VERSION 5.7 ;
  NOWIREEXTENSIONATPIN ON ;
  DIVIDERCHAR "/" ;
  BUSBITCHARS "[]" ;
PROPERTYDEFINITIONS
  MACRO ALPHA STRING ;
  MACRO MASK STRING ;
  MACRO CDL STRING ;
  MACRO ZED STRING ;
END PROPERTYDEFINITIONS

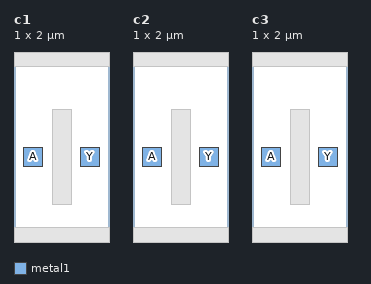
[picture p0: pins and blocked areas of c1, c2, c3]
MACRO c1
  CLASS BLOCK ;
  FOREIGN c1 ;
  ORIGIN 0.000 0.000 ;
  SIZE 1.000 BY 2.000 ;
  PIN A
    DIRECTION INPUT ;
    USE SIGNAL ;
    PORT
      LAYER metal1 ;
        RECT 0.100 0.800 0.300 1.000 ;
    END
  END A
  PIN Y
    DIRECTION OUTPUT ;
    USE SIGNAL ;
    PORT
      LAYER metal1 ;
        RECT 0.700 0.800 0.900 1.000 ;
    END
  END Y
  OBS
      LAYER metal1 ;
        RECT 0.000 1.850 1.000 2.000 ;
        RECT 0.400 0.400 0.600 1.400 ;
        RECT 0.000 0.000 1.000 0.150 ;
  END
  PROPERTY CDL c1 ;
  PROPERTY MASK 1 ;
END c1
MACRO c2
  CLASS BLOCK ;
  FOREIGN c2 ;
  ORIGIN 0.000 0.000 ;
  SIZE 1.000 BY 2.000 ;
  PIN A
    DIRECTION INPUT ;
    USE SIGNAL ;
    PORT
      LAYER metal1 ;
        RECT 0.100 0.800 0.300 1.000 ;
    END
  END A
  PIN Y
    DIRECTION OUTPUT ;
    USE SIGNAL ;
    PORT
      LAYER metal1 ;
        RECT 0.700 0.800 0.900 1.000 ;
    END
  END Y
  OBS
      LAYER metal1 ;
        RECT 0.000 1.850 1.000 2.000 ;
        RECT 0.400 0.400 0.600 1.400 ;
        RECT 0.000 0.000 1.000 0.150 ;
  END
  PROPERTY ZED 2 ;
  PROPERTY CDL c2 ;
END c2
MACRO c3
  CLASS BLOCK ;
  FOREIGN c3 ;
  ORIGIN 0.000 0.000 ;
  SIZE 1.000 BY 2.000 ;
  PIN A
    DIRECTION INPUT ;
    USE SIGNAL ;
    PORT
      LAYER metal1 ;
        RECT 0.100 0.800 0.300 1.000 ;
    END
  END A
  PIN Y
    DIRECTION OUTPUT ;
    USE SIGNAL ;
    PORT
      LAYER metal1 ;
        RECT 0.700 0.800 0.900 1.000 ;
    END
  END Y
  OBS
      LAYER metal1 ;
        RECT 0.000 1.850 1.000 2.000 ;
        RECT 0.400 0.400 0.600 1.400 ;
        RECT 0.000 0.000 1.000 0.150 ;
  END
  PROPERTY ALPHA 3 ;
END c3
MACRO top
  CLASS BLOCK ;
  FOREIGN top ;
  ORIGIN 0.000 0.000 ;
  SIZE 5.000 BY 2.000 ;
  OBS
      LAYER metal1 ;
        RECT 0.000 1.850 1.000 2.000 ;
        RECT 2.000 1.850 3.000 2.000 ;
        RECT 4.000 1.850 5.000 2.000 ;
        RECT 0.100 0.800 0.300 1.000 ;
        RECT 0.400 0.400 0.600 1.400 ;
        RECT 0.700 0.800 0.900 1.000 ;
        RECT 2.100 0.800 2.300 1.000 ;
        RECT 2.400 0.400 2.600 1.400 ;
        RECT 2.700 0.800 2.900 1.000 ;
        RECT 4.100 0.800 4.300 1.000 ;
        RECT 4.400 0.400 4.600 1.400 ;
        RECT 4.700 0.800 4.900 1.000 ;
        RECT 0.000 0.000 1.000 0.150 ;
        RECT 2.000 0.000 3.000 0.150 ;
        RECT 4.000 0.000 5.000 0.150 ;
  END
END top
END LIBRARY

